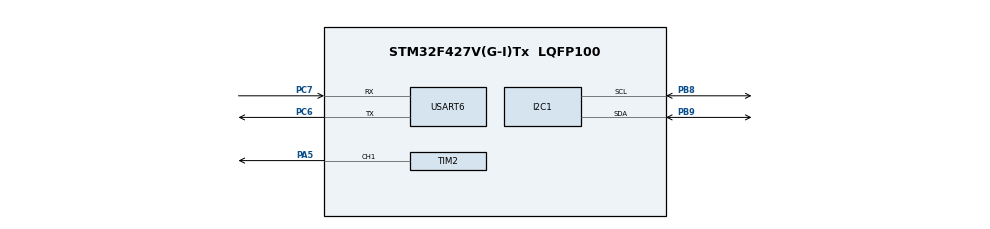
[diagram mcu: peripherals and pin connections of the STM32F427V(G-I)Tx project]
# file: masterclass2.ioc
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Mcu.Family=STM32F4
RCC.CortexFreq_Value=16000000
PC6.Signal=USART6_TX
ProjectManager.StackSize=0x400
PA13.Signal=SYS_JTMS-SWDIO
ProjectManager.TargetToolchain=STM32CubeIDE
PC6.Mode=Asynchronous
PH0/OSC_IN.Mode=HSE-External-Oscillator
PB9.Mode=I2C
PC7.Signal=USART6_RX
PH1/OSC_OUT.Signal=RCC_OSC_OUT
RCC.LSE_VALUE=32768
RCC.AHBFreq_Value=16000000
PA5.Signal=S_TIM2_CH1_ETR
RCC.HSE_VALUE=25000000
PB3.Mode=JTAG_5_pins
board=custom
RCC.VCOOutputFreq_Value=192000000
PA15.Mode=JTAG_5_pins
PH0/OSC_IN.Signal=RCC_OSC_IN
RCC.APB2Freq_Value=16000000
PB4.Mode=JTAG_5_pins
PA14.Mode=JTAG_5_pins
TIM2.Channel-PWM\ Generation1\ CH1=TIM_CHANNEL_1
TIM2.Period=10
PA13.Mode=JTAG_5_pins
PH1/OSC_OUT.Mode=HSE-External-Oscillator
Mcu.Name=STM32F427V(G-I)Tx
PB3.Signal=SYS_JTDO-SWO
RCC.SYSCLKFreq_VALUE=16000000
Mcu.Package=LQFP100
PB9.Signal=I2C1_SDA
USART6.VirtualMode=VM_ASYNC
SH.S_TIM2_CH1_ETR.0=TIM2_CH1,PWM Generation1 CH1
PA14.Signal=SYS_JTCK-SWCLK
PA15.Signal=SYS_JTDI
ProjectManager.HeapSize=0x200
RCC.HSI_VALUE=16000000
NVIC.PriorityGroup=NVIC_PRIORITYGROUP_4
PB8.Mode=I2C
PB8.Signal=I2C1_SCL
PC7.Mode=Asynchronous
RCC.APB1Freq_Value=16000000
PB4.Signal=SYS_JTRST

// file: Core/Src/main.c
/* USER CODE BEGIN Header */
/**
  ******************************************************************************
  * @file           : main.c
  * @brief          : Main program body
  ******************************************************************************
  * @attention
  *
  * <h2><center>&copy; Copyright (c) 2019 STMicroelectronics.
  * All rights reserved.</center></h2>
  *
  * This software component is licensed by ST under BSD 3-Clause license,
  * the "License"; You may not use this file except in compliance with the
  * License. You may obtain a copy of the License at:
  *                        opensource.org/licenses/BSD-3-Clause
  *
  ******************************************************************************
  */
/* USER CODE END Header */

#include "main.h"
#include "i2c.h"
#include "tim.h"
#include "usart.h"
#include "gpio.h"

/* USER CODE BEGIN Includes */
#include "kb.h"
#include "sdk_uart.h"
#include "pca9538.h"
#include "oled.h"
#include "fonts.h"
#include "tim.h"
#include "buzzer.h"
/* USER CODE END Includes */

/* USER CODE BEGIN PV */
	uint32_t sound[] = {
		100, 2000, 100, 2000, 100, 2000
	};
	uint32_t sound_delays[] = {
		50, 75, 100, 100, 75, 50
	};
/* USER CODE END PV */

void SystemClock_Config(void);
/* USER CODE BEGIN PFP */
void KB_Test( void );
void OLED_TIMER(uint8_t OLED_Keys[4]);
void TIMER_NOW( void );
void OLED_KB( uint8_t OLED_Keys[]);
void oled_Reset( void );
/* USER CODE END PFP */

int main(void)
{

  /* MCU Configuration--------------------------------------------------------*/

  /* Reset of all peripherals, Initializes the Flash interface and the Systick. */
  HAL_Init();

  /* Configure the system clock */
  SystemClock_Config();

  /* Initialize all configured peripherals */
  MX_GPIO_Init();
  MX_I2C1_Init();
  MX_USART6_UART_Init();
  MX_TIM2_Init();
  /* USER CODE BEGIN 2 */
  oled_Init();
  MX_TIM2_Init();
  Buzzer_Init();
  /* USER CODE END 2 */

  /* Infinite loop */
  while (1)
  {

    /* USER CODE BEGIN 3 */
	  TIMER_NOW();
  }
  /* USER CODE END 3 */
}

void SystemClock_Config(void)
{
  RCC_OscInitTypeDef RCC_OscInitStruct = {0};
  RCC_ClkInitTypeDef RCC_ClkInitStruct = {0};

  /** Configure the main internal regulator output voltage
  */
  __HAL_RCC_PWR_CLK_ENABLE();
  __HAL_PWR_VOLTAGESCALING_CONFIG(PWR_REGULATOR_VOLTAGE_SCALE1);
  /** Initializes the CPU, AHB and APB busses clocks
  */
  RCC_OscInitStruct.OscillatorType = RCC_OSCILLATORTYPE_HSE;
  RCC_OscInitStruct.HSEState = RCC_HSE_ON;
  RCC_OscInitStruct.PLL.PLLState = RCC_PLL_ON;
  RCC_OscInitStruct.PLL.PLLSource = RCC_PLLSOURCE_HSE;
  RCC_OscInitStruct.PLL.PLLM = 25;
  RCC_OscInitStruct.PLL.PLLN = 336;
  RCC_OscInitStruct.PLL.PLLP = RCC_PLLP_DIV2;
  RCC_OscInitStruct.PLL.PLLQ = 4;
  if (HAL_RCC_OscConfig(&RCC_OscInitStruct) != HAL_OK)
  {
    Error_Handler();
  }
  /** Initializes the CPU, AHB and APB busses clocks
  */
  RCC_ClkInitStruct.ClockType = RCC_CLOCKTYPE_HCLK|RCC_CLOCKTYPE_SYSCLK
                              |RCC_CLOCKTYPE_PCLK1|RCC_CLOCKTYPE_PCLK2;
  RCC_ClkInitStruct.SYSCLKSource = RCC_SYSCLKSOURCE_PLLCLK;
  RCC_ClkInitStruct.AHBCLKDivider = RCC_SYSCLK_DIV1;
  RCC_ClkInitStruct.APB1CLKDivider = RCC_HCLK_DIV4;
  RCC_ClkInitStruct.APB2CLKDivider = RCC_HCLK_DIV2;

  if (HAL_RCC_ClockConfig(&RCC_ClkInitStruct, FLASH_LATENCY_5) != HAL_OK)
  {
    Error_Handler();
  }
}

/* USER CODE BEGIN 4 */

void TIMER_NOW( void ){
		uint8_t Row[4] = {ROW4, ROW3, ROW2, ROW1}, Key, OldKey, OLED_Keys[4] = {0x30,0x30,0x30,0x30};
		oled_Reset();
		oled_WriteString("Timer: ", Font_11x18, White);
		OLED_TIMER(OLED_Keys);
		oled_UpdateScreen();
		uint8_t isStarted = 0, isPaused = 0, isManuallyStopped = 0;
		uint8_t position = 0;
		int count = 0;
		uint32_t timeSeconds = 0;

		uint8_t sec, sec10, min, min10;

	  while (1) {

	    if (isStarted) {
				while (timeSeconds != 0) {
					HAL_Delay(25);
					count++;
					if (!isPaused && count == 1000 / 28) {
						timeSeconds--;
						min10 = timeSeconds / 600;
						count = 0;
						min = (timeSeconds - 600 * min10) / 60;
						sec10 = (timeSeconds - 600 * min10 - 60 * min) / 10;
						sec = (timeSeconds - 600 * min10 - 60 * min - 10 * sec10);
						OLED_Keys[0] = 0x30 + sec; // 0x30 = 0
						OLED_Keys[1] = 0x30 + sec10;
						OLED_Keys[2] = 0x30 + min;
						OLED_Keys[3] = 0x30 + min10;
						OLED_TIMER(OLED_Keys);
					}

					OldKey = Key;
					Key = Get_Key( Row[0] );

					if (Key == 0x0C && OldKey != Key) {
						if (isPaused) {
							isPaused = 0;
						} else {
							isPaused = 1;
						}
						count = 0;
					}

					if (Key == 0x0B) {
					  isManuallyStopped = 1;
					  break;
					}
			  }

			  isStarted = 0;
			  position = 0;
			  OLED_Keys[0] = 0x30;
			  OLED_Keys[1] = 0x30;
			  OLED_Keys[2] = 0x30;
			  OLED_Keys[3] = 0x30;
			  OLED_TIMER(OLED_Keys);
			  if (!isManuallyStopped) {
				  Buzzer_Play_Sound(sound, sound_delays, sizeof(sound) / sizeof(uint32_t));
			  }
			  isManuallyStopped = 0;
	    }

        // 7 8 9
        // 4 5 6
        // 1 2 3
        // 0 s p
	    for (int i = 0; i < 4; i++) {
	      OldKey = Key;
	      Key = Get_Key( Row[i] );
	      if (Key != OldKey){
	        if (Key >= 0x00 && Key <= 0x0A && !isStarted) {
	          OLED_Keys[position] = 0x30 + Key;
	          if (position == 0) {
				  timeSeconds = 0;
				  OLED_Keys[1] = 0x30;
				  OLED_Keys[2] = 0x30;
				  OLED_Keys[3] = 0x30;
				  timeSeconds += Key;
				  position++;
	          } else  if (position == 1) {
	        	  timeSeconds += 10*Key;
	              position++;
	          } else if (position == 2) {
	        	  timeSeconds += 60*Key;
	              position++;
	          } else if (position == 3) {
	        	  if (Key > 5) {
	        		  Key = 5;
	        		  OLED_Keys[position] = 0x30 + Key;
	        	  }
	            timeSeconds += 600* Key;
	            position = 0;
	          }

	          OLED_TIMER(OLED_Keys);
	        } else if (Key == 0x0B) { // reset
	            break;
	        } else if (Key == 0x0C) { // toggle pause
	          if (!isStarted) {
	            isStarted  = 1;
	          } else {
	            if (isPaused) {
	              isPaused = 0;
	            } else {
	              isPaused = 1;
	            }
	          }
	        }
	      }
	      HAL_Delay(25);
	    }
	  }
}

void OLED_TIMER(uint8_t OLED_Keys[4]){
	oled_SetCursor(20, 20); //change 0 to i
	for (int i = 3; i >= 0; i--) {
			if (i == 1){
				//0x3A - ':'
				oled_WriteChar(0x3A, Font_11x18, White); //change font
			}
			oled_WriteChar(OLED_Keys[i], Font_11x18, White);
		}
		oled_UpdateScreen();
}

void KB_Test( void ) {
	UART_Transmit( (uint8_t*)"KB test start\n" );
	uint8_t R = 0, C = 0, L = 0, Row[4] = {ROW4, ROW3, ROW2, ROW1}, Key, OldKey, OLED_Keys[12] = {0x30,0x30,0x30,0x30,0x30,0x30,0x30,0x30,0x30,0x30,0x30,0x30};
	oled_Reset();
	oled_WriteString("From bottom to top", Font_7x10, White);
	OLED_KB(OLED_Keys);
	oled_UpdateScreen();
	for ( int i = 0; i < 4; i++ ) {
		while( !( R && C && L ) ) {
			OldKey = Key;
			Key = Check_Row( Row[i] );
			if ( Key == 0x01 && Key != OldKey) {
				UART_Transmit( (uint8_t*)"Right pressed\n" );
				R = 1;
				OLED_Keys[2+3*i] = 0x31;
				OLED_KB(OLED_Keys);
			} else if ( Key == 0x02 && Key != OldKey) {
				UART_Transmit( (uint8_t*)"Center pressed\n" );
				C = 1;
				OLED_Keys[1+3*i] = 0x31;
				OLED_KB(OLED_Keys);
			} else if ( Key == 0x04 && Key != OldKey) {
				UART_Transmit( (uint8_t*)"Left pressed\n" );
				L = 1;
				OLED_Keys[3*i] = 0x31;
				OLED_KB(OLED_Keys);
			}
		}
		UART_Transmit( (uint8_t*)"Row complete\n" );
		R = C = L = 0;
		HAL_Delay(25);
	}
	UART_Transmit( (uint8_t*)"KB test complete\n");
}
void OLED_KB( uint8_t OLED_Keys[12]) {
	for (int i = 3; i >= 0; i--) {
		oled_SetCursor(56, 5+(4-i)*10);
		for (int j = 0; j < 3; j++) {
			oled_WriteChar(OLED_Keys[j+3*i], Font_7x10, White);
		}
	}
	oled_UpdateScreen();
}
void oled_Reset( void ) {
	oled_Fill(Black);
	oled_SetCursor(0, 0);
	oled_UpdateScreen();
}
/* USER CODE END 4 */

void Error_Handler(void)
{
}

/************************ (C) COPYRIGHT STMicroelectronics *****END OF FILE****/
